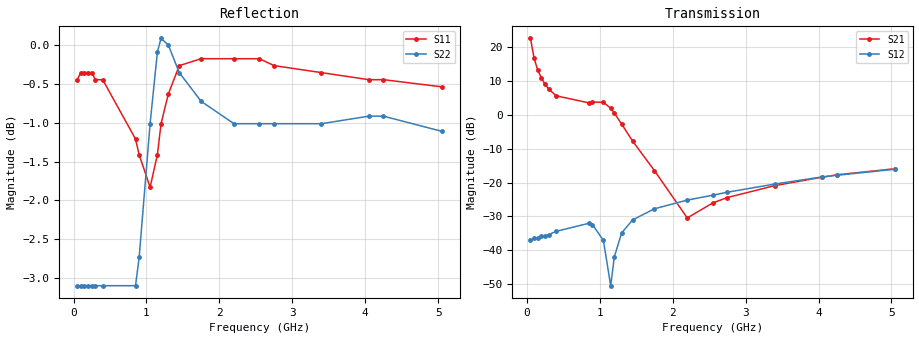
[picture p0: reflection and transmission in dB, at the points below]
!AT-36408
!S-PARAMETERS at Vce=6.0 V  Ic=150 mA.  LAST UPDATED 08-05-96
# ghz s ma r 50
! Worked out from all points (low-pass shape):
!   101 points, 50 MHz to 5.05 GHz, reference 50 ohm
!   highest |S21| = 22.56 dB at 50 MHz (marker M1); lowest = -30.5 dB at 2.2 GHz (marker M2)
!   |S21| within 3 dB of the highest: start of sweep to 75.32 MHz
!   lowest |S11| = -1.8 dB at 1.05 GHz (marker M3), VSWR 9.53, Z = 5.27 + j3.46 ohm
!   |S11| at or under -10 dB: nowhere
!   |S22| runs from -3.3 to 0.1 dB; largest |S21 - S12| = 13
!   S11 on the Smith chart (normalised r, x): 50 MHz: 0.03, -0.06; 850 MHz: 0.07, +0.10; 2.75 GHz: 0.02, +0.26; 4.05 GHz: 0.03, +0.44; 5.05 GHz: 0.04, +0.66
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0.05  0.95 -173.0  13.43 93.0  0.014 11.0  0.7 -167.0
0.1  0.96 -178.0  6.79 88.0  0.015 12.0  0.7 -173.0
0.15  0.96 -180.0  4.57 84.0  0.015 15.0  0.7 -175.0
0.2  0.96 179.0  3.48 81.0  0.016 17.0  0.7 -176.0
0.25  0.96 178.0  2.83 79.0  0.016 19.0  0.7 -176.0
0.3  0.95 177.0  2.41 76.0  0.017 21.0  0.7 -176.0
0.4  0.95 175.0  1.91 70.0  0.019 24.0  0.7 -175.0
0.85  0.87 169.0  1.5 30.0  0.025 11.0  0.7 -164.0
0.9  0.85 169.0  1.54 21.0  0.024 5.0  0.73 -162.0
1.05  0.81 172.0  1.53 -14.0  0.014 -33.0  0.89 -159.0
1.15  0.85 176.0  1.25 -43.0  0.003 -140.0  0.99 -165.0
1.2  0.89 176.0  1.06 -55.0  0.008 150.0  1.01 -168.0
1.3  0.93 174.0  0.73 -75.0  0.018 119.0  1 -173.0
1.45  0.97 170.0  0.41 -94.0  0.028 102.0  0.96 -176.0
1.75  0.98 165.0  0.15 -119.0  0.041 88.0  0.92 -178.0
2.2  0.98 158.0  0.03 173.0  0.055 80.0  0.89 -179.0
2.55  0.98 154.0  0.05 107.0  0.065 77.0  0.89 -179.0
2.75  0.97 151.0  0.06 92.0  0.072 75.0  0.89 -179.0
3.4  0.96 142.0  0.09 73.0  0.095 70.0  0.89 179.0
4.05  0.95 132.0  0.12 61.0  0.121 61.0  0.9 176.0
4.25  0.95 129.0  0.13 59.0  0.128 58.0  0.9 174.0
5.05  0.94 113.0  0.16 47.0  0.157 48.0  0.88 168.0
